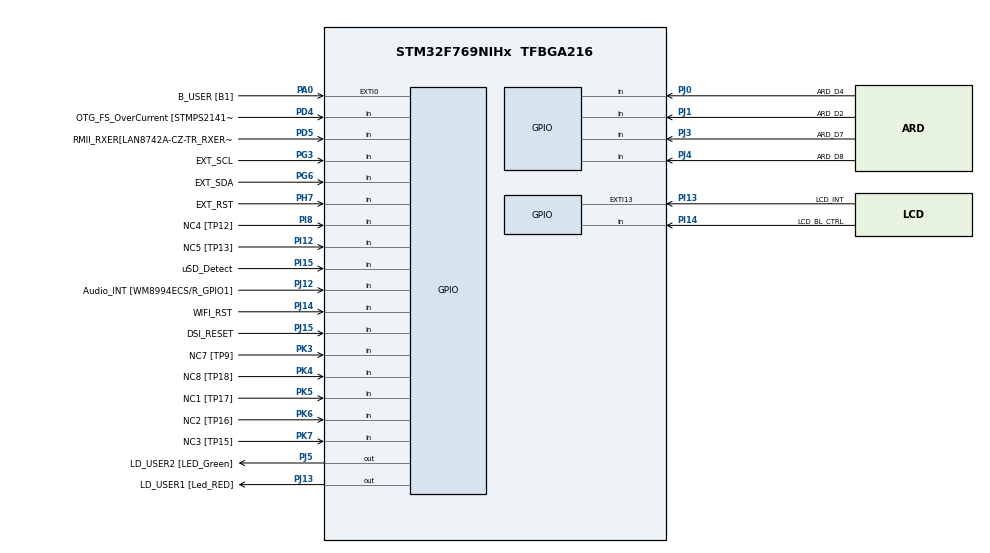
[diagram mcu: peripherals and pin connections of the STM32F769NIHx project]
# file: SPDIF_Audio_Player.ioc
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DSIHOST_CKN.GPIO_Label=DSI_CK_N
DSIHOST_CKN.Signal=DSIHOST_CKN
DSIHOST_CKP.GPIO_Label=DSI_CK_P
DSIHOST_CKP.Signal=DSIHOST_CKP
DSIHOST_D0N.GPIO_Label=DSI_D0_N
DSIHOST_D0N.Signal=DSIHOST_D0N
DSIHOST_D0P.GPIO_Label=DSI_D0_p
DSIHOST_D0P.Signal=DSIHOST_D0P
DSIHOST_D1N.GPIO_Label=DSI_D1_N
DSIHOST_D1N.Signal=DSIHOST_D1N
DSIHOST_D1P.GPIO_Label=DSI_D1_P
DSIHOST_D1P.Signal=DSIHOST_D1P
Mcu.Family=STM32F7
Mcu.Name=STM32F769NIHx
Mcu.Package=TFBGA216
NVIC.PriorityGroup=NVIC_PRIORITYGROUP_4
PA0/WKUP.GPIO_Label=B_USER [B1]
PA0/WKUP.Signal=GPXTI0
PA1.GPIO_Label=RMII_REF_CLK [LAN8742A-CZ-TR_REFCLK0]
PA1.Signal=ETH_REF_CLK
PA10.GPIO_Label=VCP_RX 
PA10.Signal=USART1_RX
PA11.GPIO_Label=SPI2_NSS
PA11.Signal=SPI2_NSS
PA12.GPIO_Label=ARD_D13/SCK
PA12.GPIO_Mode=GPIO_MODE_AF_PP
PA12.GPIO_PuPd=GPIO_NOPULL
PA12.GPIO_Speed=GPIO_SPEED_FREQ_LOW
PA12.Signal=SPI2_SCK
PA13.GPIO_Label=SWDIO
PA13.Signal=SYS_JTMS-SWDIO
PA14.GPIO_Label=SWCLK
PA14.Signal=SYS_JTCK-SWCLK
PA15.GPIO_Label=CEC
PA15.Signal=CEC
PA2.GPIO_Label=RMII_MDIO [LAN8742A-CZ-TR_MDIO]
PA2.Signal=ETH_MDIO
PA3.GPIO_Label=ULPI_D0 [USB3320C-EZK_D0]
PA3.Signal=USB_OTG_HS_ULPI_D0
PA4.GPIO_Label=ARD_A1
PA4.Signal=ADCx_IN4
PA5.GPIO_Label=ULPI_CLK [USB3320C-EZK_CLKOUT]
PA5.Signal=USB_OTG_HS_ULPI_CK
PA6.GPIO_Label=ARD_A0
PA6.Signal=ADCx_IN6
PA7.GPIO_Label=RMII_CRS_DV [LAN8742A-CZ-TR_CRS_DV]
PA7.Signal=ETH_CRS_DV
PA8.GPIO_Label=CEC_CLK [TP2]
PA8.Signal=RCC_MCO_1
PA9.GPIO_Label=VCP_TX [STM32F103CBT6_PA3]
PA9.GPIO_Mode=GPIO_MODE_AF_PP
PA9.GPIO_PuPd=GPIO_NOPULL
PA9.GPIO_Speed=GPIO_SPEED_FREQ_LOW
PA9.Signal=USART1_TX
PB0.GPIO_Label=ULPI_D1 [USB3320C-EZK_D1]
PB0.Signal=USB_OTG_HS_ULPI_D1
PB1.GPIO_Label=ULPI_D2 [USB3320C-EZK_D2]
PB1.Signal=USB_OTG_HS_ULPI_D2
PB10.GPIO_Label=ULPI_D3 [USB3320C-EZK_D3]
PB10.Signal=USB_OTG_HS_ULPI_D3
PB11.GPIO_Label=ULPI_D4 [USB3320C-EZK_D4]
PB11.Signal=USB_OTG_HS_ULPI_D4
PB12.GPIO_Label=ULPI_D5 [USB3320C-EZK_D5]
PB12.Signal=USB_OTG_HS_ULPI_D5
PB13.GPIO_Label=ULPI_D6 [USB3320C-EZK_D6]
PB13.Signal=USB_OTG_HS_ULPI_D6
PB14.GPIO_Label=ARDUINO MISO/D12
PB14.GPIO_Mode=GPIO_MODE_AF_PP
PB14.GPIO_PuPd=GPIO_NOPULL
PB14.GPIO_Speed=GPIO_SPEED_FREQ_LOW
PB14.Signal=SPI2_MISO
PB15.GPIO_Label=ARDUINO MOSI/PWM/D11
PB15.GPIO_Mode=GPIO_MODE_AF_PP
PB15.GPIO_PuPd=GPIO_NOPULL
PB15.GPIO_Speed=GPIO_SPEED_FREQ_LOW
PB15.Signal=SPI2_MOSI
PB2.Signal=QUADSPI_CLK
PB3.GPIO_Label=uSD_D2
PB3.Signal=SDMMC2_D2
PB4.GPIO_Label=uSD_D3
PB4.Signal=SDMMC2_D3
PB5.GPIO_Label=ULPI_D7 [USB3320C-EZK_D7]
PB5.Signal=USB_OTG_HS_ULPI_D7
PB6.GPIO_Label=QSPI_NCS [N25Q128A13EF840E_S]
PB6.Signal=QUADSPI_BK1_NCS
PB7.GPIO_Label=AUDIO_SDA [WM8994ECS/R_SDA]
PB7.Signal=I2C4_SDA
PB8.GPIO_Label=ARDUINO SCL/D15
PB8.GPIO_Mode=GPIO_MODE_AF_OD
PB8.GPIO_PuPd=GPIO_NOPULL
PB8.GPIO_Speed=GPIO_SPEED_FREQ_LOW
PB8.Signal=I2C1_SCL
PB9.GPIO_Label=ARDUINO SDA/D14
PB9.GPIO_Mode=GPIO_MODE_AF_OD
PB9.GPIO_PuPd=GPIO_NOPULL
PB9.GPIO_Speed=GPIO_SPEED_FREQ_LOW
PB9.Signal=I2C1_SDA
PC0.GPIO_Label=ULPI_STP [USB3320C-EZK_STP]
PC0.Signal=USB_OTG_HS_ULPI_STP
PC1.GPIO_Label=RMII_MDC [LAN8742A-CZ-TR_MDC]
PC1.Signal=ETH_MDC
PC10.GPIO_Label=QSPI_D1 [MT25QL512ABB1EW9_DQ1]
PC10.Signal=QUADSPI_BK1_IO1
PC11.GPIO_Label=DFSDM_DATIN5 [TP100]
PC11.Signal=S_DATAIN5DFSDM1
PC12.GPIO_Label=WIFI_RX
PC12.Signal=UART5_TX
PC14/OSC32_IN.GPIO_Label=RCC_OSC32_IN
PC14/OSC32_IN.Signal=RCC_OSC32_IN
PC15/OSC32_OUT.GPIO_Label=RCC_OSC32_OUT
PC15/OSC32_OUT.Signal=RCC_OSC32_OUT
PC2.GPIO_Label=ARD_A2
PC2.Signal=ADCx_IN12
PC3.GPIO_Label=DFSDM_DATIN1 [TP101]
PC3.Signal=S_DATAIN1DFSDM1
PC4.GPIO_Label=RMII_RXD0 [LAN8742A-CZ-TR_RXD0]
PC4.Signal=ETH_RXD0
PC5.GPIO_Label=RMII_RXD1 [LAN8742A-CZ-TR_RXD1]
PC5.Signal=ETH_RXD1
PC6.GPIO_Label=ARDUINO TX/D1
PC6.Signal=USART6_TX
PC7.GPIO_Label=ARD_D0/RX
PC7.Signal=USART6_RX
PC8.GPIO_Label=ARD_D5/PWM
PC8.Signal=S_TIM3_CH3
PC9.GPIO_Label=QSPI_D0 [N25Q128A13EF840E_DQ0]
PC9.Signal=QUADSPI_BK1_IO0
PD0.GPIO_Label=FMC_D2 [MT48LC4M32B2B5-6A_DQ2]
PD0.Signal=FMC_D2_DA2
PD1.GPIO_Label=FMC_D3 [MT48LC4M32B2B5-6A_DQ3]
PD1.Signal=FMC_D3_DA3
PD10.GPIO_Label=FMC_D15 [MT48LC4M32B2B5-6A_DQ15]
PD10.Signal=FMC_D15_DA15
PD11.GPIO_Label=SPDIF_TX [TP20]
PD11.Signal=SAI2_SD_A
PD12.GPIO_Label=AUDIO_SCL [WM8994ECS/R_SCLK]
PD12.Signal=I2C4_SCL
PD13.GPIO_Label=QSPI_D3 [N25Q128A13EF840E_DQ3]
PD13.Signal=QUADSPI_BK1_IO3
PD14.GPIO_Label=FMC_D0 [MT48LC4M32B2B5-6A_DQ0]
PD14.Signal=FMC_D0_DA0
PD15.GPIO_Label=FMC_D1 [MT48LC4M32B2B5-6A_DQ1]
PD15.Signal=FMC_D1_DA1
PD2.GPIO_Label=WIFI_TX
PD2.Signal=UART5_RX
PD3.GPIO_Label=DFSDM_CKOUT [TP102]
PD3.Signal=S_CKOUTDFSDM1
PD4.GPIO_Label=OTG_FS_OverCurrent [STMPS2141STR_Fault]
PD4.Signal=GPIO_Input
PD5.GPIO_Label=RMII_RXER[LAN8742A-CZ-TR_RXERR]
PD5.Signal=GPIO_Input
PD6.GPIO_Label=uSD_CLK
PD6.Signal=SDMMC2_CK
PD7.GPIO_Label=uSD_CMD
PD7.Signal=SDMMC2_CMD
PD8.GPIO_Label=FMC_D13 [MT48LC4M32B2B5-6A_DQ13]
PD8.Signal=FMC_D13_DA13
PD9.GPIO_Label=FMC_D14 [MT48LC4M32B2B5-6A_DQ14]
PD9.Signal=FMC_D14_DA14
PE0.GPIO_Label=FMC_NBL0 [MT48LC4M32B2B5-6A_DQM0]
PE0.Signal=FMC_NBL0
PE1.GPIO_Label=FMC_NBL1 [MT48LC4M32B2B5-6A_DQM1]
PE1.Signal=FMC_NBL1
PE10.GPIO_Label=FMC_D7 [MT48LC4M32B2B5-6A_DQ7]
PE10.Signal=FMC_D7_DA7
PE11.GPIO_Label=FMC_D8 [MT48LC4M32B2B5-6A_DQ8]
PE11.Signal=FMC_D8_DA8
PE12.GPIO_Label=FMC_D9 [MT48LC4M32B2B5-6A_DQ9]
PE12.Signal=FMC_D9_DA9
PE13.GPIO_Label=FMC_D10 [MT48LC4M32B2B5-6A_DQ10]
PE13.Signal=FMC_D10_DA10
PE14.GPIO_Label=FMC_D11 [MT48LC4M32B2B5-6A_DQ11]
PE14.Signal=FMC_D11_DA11
PE15.GPIO_Label=FMC_D12 [MT48LC4M32B2B5-6A_DQ12]
PE15.Signal=FMC_D12_DA12
PE2.GPIO_Label=QSPI_D2 [N25Q128A13EF840E_DQ2]
PE2.Signal=QUADSPI_BK1_IO2
PE3.GPIO_Label=SAI1_SDB [WM8994ECS/R_ADCDAT1]
PE3.Signal=SAI1_SD_B
PE4.GPIO_Label=SAI1_FSA [WM8994ECS/R_LRCLK1]
PE4.Signal=SAI1_FS_A
PE5.GPIO_Label=SAI1_SCKA [WM8994ECS/R_BCLK1]
PE5.Signal=SAI1_SCK_A
PE6.GPIO_Label=SAI1_SDA [WM8994ECS/R_DACDAT1]
PE6.Signal=SAI1_SD_A
PE7.GPIO_Label=FMC_D4 [MT48LC4M32B2B5-6A_DQ4]
PE7.Signal=FMC_D4_DA4
PE8.GPIO_Label=FMC_D5 [MT48LC4M32B2B5-6A_DQ5]
PE8.Signal=FMC_D5_DA5
PE9.GPIO_Label=FMC_D6 [MT48LC4M32B2B5-6A_DQ6]
PE9.Signal=FMC_D6_DA6
PF0.GPIO_Label=FMC_A0 [MT48LC4M32B2B5-6A_A0]
PF0.Signal=FMC_A0
PF1.GPIO_Label=FMC_A1 [MT48LC4M32B2B5-6A_A1]
PF1.Signal=FMC_A1
PF10.GPIO_Label=ARDUINO A1
PF10.GPIO_Mode=GPIO_MODE_ANALOG
PF10.GPIO_PuPd=GPIO_NOPULL
PF10.Signal=ADC3_IN8
PF11.GPIO_Label=FMC_SDNRAS [MT48LC4M32B2B5-6A_RAS]
PF11.Signal=FMC_SDNRAS
PF12.GPIO_Label=FMC_A6 [MT48LC4M32B2B5-6A_A6]
PF12.Signal=FMC_A6
PF13.GPIO_Label=FMC_A7 [MT48LC4M32B2B5-6A_A7]
PF13.Signal=FMC_A7
PF14.GPIO_Label=FMC_A8 [MT48LC4M32B2B5-6A_A8]
PF14.Signal=FMC_A8
PF15.GPIO_Label=FMC_A9 [MT48LC4M32B2B5-6A_A9]
PF15.Signal=FMC_A9
PF2.GPIO_Label=FMC_A2 [MT48LC4M32B2B5-6A_A2]
PF2.Signal=FMC_A2
PF3.GPIO_Label=FMC_A3 [MT48LC4M32B2B5-6A_A3]
PF3.Signal=FMC_A3
PF4.GPIO_Label=FMC_A4 [MT48LC4M32B2B5-6A_A4]
PF4.Signal=FMC_A4
PF5.GPIO_Label=FMC_A5 [MT48LC4M32B2B5-6A_A5]
PF5.Signal=FMC_A5
PF6.GPIO_Label=ARD_D3/PWM
PF6.Signal=S_TIM10_CH1
PF7.GPIO_Label=ARD_D6/PWM
PF7.Signal=S_TIM11_CH1
PF8.GPIO_Label=ARDUINO A3
PF8.GPIO_Mode=GPIO_MODE_ANALOG
PF8.GPIO_PuPd=GPIO_NOPULL
PF8.Signal=ADC3_IN6
PF9.GPIO_Label=ARDUINO A2
PF9.GPIO_Mode=GPIO_MODE_ANALOG
PF9.GPIO_PuPd=GPIO_NOPULL
PF9.Signal=ADC3_IN7
PG0.GPIO_Label=FMC_A10 [MT48LC4M32B2B5-6A_A10]
PG0.Signal=FMC_A10
PG1.GPIO_Label=FMC_A11 [MT48LC4M32B2B5-6A_A11]
PG1.Signal=FMC_A11
PG10.GPIO_Label=uSD_D1
PG10.Signal=SDMMC2_D1
PG11.GPIO_Label=RMII_TX_EN [LAN8742A-CZ-TR_TXEN]
PG11.Signal=ETH_TX_EN
PG12.GPIO_Label=SPDIF_RX [74LVC1G04SE_4]
PG12.Signal=SPDIFRX_IN1
PG13.GPIO_Label=RMII_TXD0 [LAN8742A-CZ-TR_TXD0]
PG13.Signal=ETH_TXD0
PG14.GPIO_Label=RMII_TXD1 [LAN8742A-CZ-TR_TXD1]
PG14.Signal=ETH_TXD1
PG15.GPIO_Label=FMC_SDNCAS [MT48LC4M32B2B5-6A_CAS]
PG15.Signal=FMC_SDNCAS
PG2.GPIO_Label=FMC_A12
PG2.Signal=FMC_A12
PG3.GPIO_Label=EXT_SCL
PG3.Signal=GPIO_Input
PG4.GPIO_Label=FMC_BA0 [MT48LC4M32B2B5-6A_BA0]
PG4.Signal=FMC_A14_BA0
PG5.GPIO_Label=FMC_BA1 [MT48LC4M32B2B5-6A_BA1]
PG5.Signal=FMC_A15_BA1
PG6.GPIO_Label=EXT_SDA
PG6.Signal=GPIO_Input
PG7.GPIO_Label=SAI1_MCLKA [WM8994ECS/R_MCLK1]
PG7.Signal=SAI1_MCLK_A
PG8.GPIO_Label=FMC_SDCLK [MT48LC4M32B2B5-6A_CLK]
PG8.Signal=FMC_SDCLK
PG9.GPIO_Label=uSD_D0
PG9.Signal=SDMMC2_D0
PH0/OSC_IN.GPIO_Label=OSC_25M [NZ2520SB-25.00M_OUT]
PH0/OSC_IN.Signal=RCC_OSC_IN
PH1/OSC_OUT.Signal=RCC_OSC_OUT
PH10.GPIO_Label=FMC_D18 [MT48LC4M32B2B5-6A_DQ18]
PH10.Signal=FMC_D18
PH11.GPIO_Label=FMC_D19 [MT48LC4M32B2B5-6A_DQ19]
PH11.Signal=FMC_D19
PH12.GPIO_Label=D20
PH12.Signal=FMC_D20
PH13.GPIO_Label=D21
PH13.Signal=FMC_D21
PH14.GPIO_Label=D22
PH14.Signal=FMC_D22
PH15.GPIO_Label=D23
PH15.Signal=FMC_D23
PH2.GPIO_Label=FMC_SDCKE0 [MT48LC4M32B2B5-6A_CKE]
PH2.Signal=FMC_SDCKE0
PH3.GPIO_Label=FMC_SDNE0 [MT48LC4M32B2B5-6A_CS]
PH3.Signal=FMC_SDNE0
PH4.GPIO_Label=ULPI_NXT [USB3320C-EZK_NXT]
PH4.Signal=USB_OTG_HS_ULPI_NXT
PH5.GPIO_Label=FMC_SDNME [MT48LC4M32B2B5-6A_WE]
PH5.Signal=FMC_SDNWE
PH6.GPIO_Label=ARDUINO PWM/D6
PH6.Signal=S_TIM12_CH1
PH7.GPIO_Label=EXT_RST
PH7.Signal=GPIO_Input
PH8.GPIO_Label=FMC_D16 [MT48LC4M32B2B5-6A_DQ16]
PH8.Signal=FMC_D16
PH9.GPIO_Label=FMC_D\!7 [MT48LC4M32B2B5-6A_DQ17]
PH9.Signal=FMC_D17
PI0.GPIO_Label=D24
PI0.Signal=FMC_D24
PI1.GPIO_Label=D25
PI1.Signal=FMC_D25
PI10.GPIO_Label=D31
PI10.Signal=FMC_D31
PI11.GPIO_Label=ULPI_DIR [USB3320C-EZK_DIR]
PI11.Signal=USB_OTG_HS_ULPI_DIR
PI12.GPIO_Label=NC5 [TP13]
PI12.Signal=GPIO_Input
PI13.GPIO_Label=LCD_INT
PI13.GPIO_ModeDefaultEXTI=GPIO_MODE_EVT_RISING
PI13.Signal=GPXTI13
PI14.GPIO_Label=LCD_BL_CTRL
PI14.Signal=GPIO_Input
PI15.GPIO_Label=uSD_Detect
PI15.Signal=GPIO_Input
PI2.GPIO_Label=D26
PI2.Signal=FMC_D26
PI3.GPIO_Label=D27
PI3.Signal=FMC_D27
PI4.GPIO_Label=FMC_NBL2 [MT48LC4M32B2B5-6A_DQM2]
PI4.Signal=FMC_NBL2
PI5.GPIO_Label=FMC_NBL3 [MT48LC4M32B2B5-6A_DQM3]
PI5.Signal=FMC_NBL3
PI6.GPIO_Label=D28
PI6.Signal=FMC_D28
PI7.GPIO_Label=D29
PI7.Signal=FMC_D29
PI8.GPIO_Label=NC4 [TP12]
PI8.Signal=GPIO_Input
PI9.GPIO_Label=D30
PI9.Signal=FMC_D30
PJ0.GPIO_Label=ARD_D4
PJ0.Signal=GPIO_Input
PJ1.GPIO_Label=ARD_D2
PJ1.Signal=GPIO_Input
PJ12.GPIO_Label=Audio_INT [WM8994ECS/R_GPIO1]
PJ12.Signal=GPIO_Input
PJ13.GPIO_Label=LD_USER1 [Led_RED]
PJ13.Signal=GPIO_Output
PJ14.GPIO_Label=WIFI_RST
PJ14.Signal=GPIO_Input
PJ15.GPIO_Label=DSI_RESET
PJ15.Signal=GPIO_Input
PJ2.GPIO_Label=DSIHOST_TE
PJ2.Signal=DSIHOST_TE
PJ3.GPIO_Label=ARD_D7
PJ3.Signal=GPIO_Input
PJ4.GPIO_Label=ARD_D8
PJ4.Signal=GPIO_Input
PJ5.GPIO_Label=LD_USER2 [LED_Green]
PJ5.Signal=GPIO_Output
PK3.GPIO_Label=NC7 [TP9]
PK3.Signal=GPIO_Input
PK4.GPIO_Label=NC8 [TP18]
PK4.Signal=GPIO_Input
PK5.GPIO_Label=NC1 [TP17]
PK5.Signal=GPIO_Input
PK6.GPIO_Label=NC2 [TP16]
PK6.Signal=GPIO_Input
PK7.GPIO_Label=NC3 [TP15]
PK7.Signal=GPIO_Input
ProjectManager.HeapSize=0x200
ProjectManager.StackSize=0x400
ProjectManager.TargetToolchain=STM32CubeIDE
RCC.AHBFreq_Value=96000000
RCC.APB1CLKDivider=RCC_HCLK_DIV4
RCC.APB1Freq_Value=24000000
RCC.APB1TimFreq_Value=48000000
RCC.APB2CLKDivider=RCC_HCLK_DIV2
RCC.APB2Freq_Value=48000000
RCC.APB2TimFreq_Value=96000000
RCC.CortexFreq_Value=96000000
RCC.HCLKFreq_Value=96000000
RCC.HSE_VALUE=25000000
RCC.HSI_VALUE=16000000
RCC.LSE_VALUE=32768
RCC.PLLM=8
RCC.PLLP=RCC_PLLP_DIV4
RCC.PLLQ=4
RCC.PLLSAIQ=3
RCC.SYSCLKFreq_VALUE=96000000
RCC.SYSCLKSource=RCC_SYSCLKSOURCE_PLLCLK
RCC.USBFreq_Value=96000000
RCC.VCOOutputFreq_Value=384000000
SH.ADCx_IN12.0=ADC1_IN12
SH.ADCx_IN4.0=ADC1_IN4
SH.ADCx_IN6.0=ADC1_IN6
SH.FMC_A0.0=FMC_A0
SH.FMC_A1.0=FMC_A1
SH.FMC_A10.0=FMC_A10
SH.FMC_A11.0=FMC_A11
SH.FMC_A12.0=FMC_A12
SH.FMC_A14_BA0.0=FMC_BA0
SH.FMC_A15_BA1.0=FMC_BA1
SH.FMC_A2.0=FMC_A2
SH.FMC_A3.0=FMC_A3
SH.FMC_A4.0=FMC_A4
SH.FMC_A5.0=FMC_A5
SH.FMC_A6.0=FMC_A6
SH.FMC_A7.0=FMC_A7
SH.FMC_A8.0=FMC_A8
SH.FMC_A9.0=FMC_A9
SH.FMC_D0_DA0.0=FMC_D0
SH.FMC_D10_DA10.0=FMC_D10
SH.FMC_D11_DA11.0=FMC_D11
SH.FMC_D12_DA12.0=FMC_D12
SH.FMC_D13_DA13.0=FMC_D13
SH.FMC_D14_DA14.0=FMC_D14
SH.FMC_D15_DA15.0=FMC_D15
SH.FMC_D16.0=FMC_D16
SH.FMC_D17.0=FMC_D17
SH.FMC_D18.0=FMC_D18
SH.FMC_D19.0=FMC_D19
SH.FMC_D1_DA1.0=FMC_D1
SH.FMC_D20.0=FMC_D20
SH.FMC_D21.0=FMC_D21
SH.FMC_D22.0=FMC_D22
SH.FMC_D23.0=FMC_D23
SH.FMC_D24.0=FMC_D24
SH.FMC_D25.0=FMC_D25
SH.FMC_D26.0=FMC_D26
SH.FMC_D27.0=FMC_D27
SH.FMC_D28.0=FMC_D28
SH.FMC_D29.0=FMC_D29
SH.FMC_D2_DA2.0=FMC_D2
SH.FMC_D30.0=FMC_D30
SH.FMC_D31.0=FMC_D31
SH.FMC_D3_DA3.0=FMC_D3
SH.FMC_D4_DA4.0=FMC_D4
SH.FMC_D5_DA5.0=FMC_D5
SH.FMC_D6_DA6.0=FMC_D6
SH.FMC_D7_DA7.0=FMC_D7
SH.FMC_D8_DA8.0=FMC_D8
SH.FMC_D9_DA9.0=FMC_D9
SH.FMC_NBL0.0=FMC_NBL0
SH.FMC_NBL1.0=FMC_NBL1
SH.FMC_NBL2.0=FMC_NBL2
SH.FMC_NBL3.0=FMC_NBL3
SH.FMC_SDCLK.0=FMC_SDCLK
SH.FMC_SDNCAS.0=FMC_SDNCAS
SH.FMC_SDNRAS.0=FMC_SDNRAS
SH.FMC_SDNWE.0=FMC_SDNWE
SH.S_CKOUTDFSDM1.0=DFSDM1_CKOUT
SH.S_DATAIN1DFSDM1.0=DFSDM1_DATIN1
SH.S_DATAIN5DFSDM1.0=DFSDM1_DATIN5
SH.S_TIM10_CH1.0=TIM10_CH1
SH.S_TIM11_CH1.0=TIM11_CH1
SH.S_TIM12_CH1.0=TIM12_CH1
SH.S_TIM3_CH3.0=TIM3_CH3
board=STM32F769I-DISCO

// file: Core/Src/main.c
/* USER CODE BEGIN Header */
/**
  ******************************************************************************
  * @file           : main.c
  * @brief          : Main program body
  ******************************************************************************
  * @attention
  *
  * Copyright (c) 2022 STMicroelectronics.
  * All rights reserved.
  *
  * This software is licensed under terms that can be found in the LICENSE file
  * in the root directory of this software component.
  * If no LICENSE file comes with this software, it is provided AS-IS.
  *
  ******************************************************************************
  */
/* USER CODE END Header */
#include "tasks.h"
#include "stlogo.h"
/* USER CODE END Includes */

/* USER CODE BEGIN PV */
__IO uint8_t DemoIndex = 0;
__IO uint8_t NbLoop = 1;
__IO uint32_t SdmmcTest = 0;
__IO uint32_t SdramTest = 0;

SemaphoreHandle_t xSemaphoreAudioOUT = NULL;
SemaphoreHandle_t xSemaphoreLCD = NULL;

/* USER CODE END PV */

void SystemClock_Config(void);
static void MPU_Config(void);
void SystemClock_Config(void);
static void CPU_CACHE_Enable(void);

osThreadId_t defaultTaskHandle; //Used for displaying VU Meter or something else to LCD
osThreadId_t starterTaskHandle; //Used to setup SPDIF, wait for signal disconnect
osThreadId_t playerTaskHandle;  //Used to feeding audio to SAI

const osThreadAttr_t defaultTask_attributes = {
		  .name = "defaultTask",
		  .stack_size = 512 * 4,
		  .priority = (osPriority_t) osPriorityNormal,		// osPriorityLow,
		};
const osThreadAttr_t starterTask_attributes = {
		  .name = "starterTask",
		  .stack_size = 512 * 4,
		  .priority = (osPriority_t) osPriorityNormal,		//osPriorityHigh,
		};
const osThreadAttr_t playerTask_attributes = {
		  .name = "playerTask",
		  .stack_size = 512 * 4,
		  .priority = (osPriority_t) osPriorityNormal,
		};

int main(void)
{
  /* USER CODE BEGIN 1 */

  /* Configure the MPU attributes */
  MPU_Config();

  /* Enable the CPU Cache */
  CPU_CACHE_Enable();
  /* USER CODE END 1 */

  /* MCU Configuration--------------------------------------------------------*/

  /* Reset of all peripherals, Initializes the Flash interface and the Systick. */
  HAL_Init();

  /* Configure the system clock */
  SystemClock_Config();

  /* USER CODE BEGIN 2 */
  BSP_LED_Init(LED_GREEN);
  BSP_LED_Init(LED_RED);

  /* Configure the Tamper push-button in GPIO Mode */
  BSP_PB_Init(BUTTON_WAKEUP, BUTTON_MODE_GPIO);

#if IT_FAILS_THIS_WAY
  BSP_AUDIO_OUT_Init(OUTPUT_DEVICE_HEADPHONE /*OUTPUT_DEVICE_AUTO*/, 90, 48000);
#endif

#if 1
  {
	  /* Initialize the LCD */
	  uint8_t  lcd_status = LCD_OK;
	  lcd_status = BSP_LCD_Init();
	  while(lcd_status != LCD_OK);

	  BSP_LCD_LayerDefaultInit(0, LCD_FB_START_ADDRESS);
	  BSP_LCD_Clear(LCD_COLOR_WHITE);
	  /* Set LCD Foreground Layer  */
	  BSP_LCD_SelectLayer(0);
	  BSP_LCD_SetFont(&LCD_DEFAULT_FONT);
	  /* Clear the LCD */
	  BSP_LCD_SetBackColor(LCD_COLOR_WHITE);
	  BSP_LCD_Clear(LCD_COLOR_WHITE);
  }
#endif

  /* USER CODE END 2 */

  /* Init scheduler */
  osKernelInitialize();

  /* Create the thread(s) */
  /* creation of defaultTask */

  vSemaphoreCreateBinary(xSemaphoreAudioOUT);
  xSemaphoreTake(xSemaphoreAudioOUT, 0);
  vSemaphoreCreateBinary(xSemaphoreLCD);
  xSemaphoreTake(xSemaphoreLCD, 0);

  defaultTaskHandle = osThreadNew(StartDefaultTask, NULL, &defaultTask_attributes); //Used for displaying VU Meter or something else to LCD
  playerTaskHandle = osThreadNew(playerTask, NULL, &playerTask_attributes); //Used to feeding audio to SAI
  starterTaskHandle = osThreadNew(starterTask, NULL, &starterTask_attributes); //Used to setup SPDIF, wait for signal disconnect

  /* Start scheduler */
  osKernelStart();

  /* We should never get here as control is now taken by the scheduler */
  /* Infinite loop */
  while (1)
  {

  }
}

void SystemClock_Config(void)
{
  RCC_ClkInitTypeDef RCC_ClkInitStruct;
  RCC_OscInitTypeDef RCC_OscInitStruct;
  HAL_StatusTypeDef ret = HAL_OK;

  /* Enable HSE Oscillator and activate PLL with HSE as source */
  RCC_OscInitStruct.OscillatorType = RCC_OSCILLATORTYPE_HSE;
  RCC_OscInitStruct.HSEState = RCC_HSE_ON;
  RCC_OscInitStruct.PLL.PLLState = RCC_PLL_ON;
  RCC_OscInitStruct.PLL.PLLSource = RCC_PLLSOURCE_HSE;
  RCC_OscInitStruct.PLL.PLLM = 25;
  RCC_OscInitStruct.PLL.PLLN = 400;
  RCC_OscInitStruct.PLL.PLLP = RCC_PLLP_DIV2;
  RCC_OscInitStruct.PLL.PLLQ = 8;
  RCC_OscInitStruct.PLL.PLLR = 7;

  ret = HAL_RCC_OscConfig(&RCC_OscInitStruct);
  if(ret != HAL_OK)
  {
    while(1) { ; }
  }

  /* Activate the OverDrive to reach the 200 MHz Frequency */
  ret = HAL_PWREx_EnableOverDrive();
  if(ret != HAL_OK)
  {
    while(1) { ; }
  }

  /* Select PLL as system clock source and configure the HCLK, PCLK1 and PCLK2 clocks dividers */
  RCC_ClkInitStruct.ClockType = (RCC_CLOCKTYPE_SYSCLK | RCC_CLOCKTYPE_HCLK | RCC_CLOCKTYPE_PCLK1 | RCC_CLOCKTYPE_PCLK2);
  RCC_ClkInitStruct.SYSCLKSource = RCC_SYSCLKSOURCE_PLLCLK;
  RCC_ClkInitStruct.AHBCLKDivider = RCC_SYSCLK_DIV1;
  RCC_ClkInitStruct.APB1CLKDivider = RCC_HCLK_DIV4;
  RCC_ClkInitStruct.APB2CLKDivider = RCC_HCLK_DIV2;

  ret = HAL_RCC_ClockConfig(&RCC_ClkInitStruct, FLASH_LATENCY_6);
  if(ret != HAL_OK)
  {
    while(1) { ; }
  }
}

/* USER CODE BEGIN 4 */

/**
  * @brief  Configure the MPU attributes
  * @param  None
  * @retval None
  */
static void MPU_Config(void)
{
  MPU_Region_InitTypeDef MPU_InitStruct;

  /* Disable the MPU */
  HAL_MPU_Disable();

  /* Configure the MPU as Strongly ordered for not defined regions */
  MPU_InitStruct.Enable = MPU_REGION_ENABLE;
  MPU_InitStruct.BaseAddress = 0x00;
  MPU_InitStruct.Size = MPU_REGION_SIZE_4GB;
  MPU_InitStruct.AccessPermission = MPU_REGION_NO_ACCESS;
  MPU_InitStruct.IsBufferable = MPU_ACCESS_NOT_BUFFERABLE;
  MPU_InitStruct.IsCacheable = MPU_ACCESS_NOT_CACHEABLE;
  MPU_InitStruct.IsShareable = MPU_ACCESS_SHAREABLE;
  MPU_InitStruct.Number = MPU_REGION_NUMBER0;
  MPU_InitStruct.TypeExtField = MPU_TEX_LEVEL0;
  MPU_InitStruct.SubRegionDisable = 0x87;
  MPU_InitStruct.DisableExec = MPU_INSTRUCTION_ACCESS_DISABLE;

  HAL_MPU_ConfigRegion(&MPU_InitStruct);

  /* Configure the MPU attributes as WT for SDRAM */
  MPU_InitStruct.Enable = MPU_REGION_ENABLE;
  MPU_InitStruct.BaseAddress = 0xC0000000;
  MPU_InitStruct.Size = MPU_REGION_SIZE_32MB;
  MPU_InitStruct.AccessPermission = MPU_REGION_FULL_ACCESS;
  MPU_InitStruct.IsBufferable = MPU_ACCESS_NOT_BUFFERABLE;
  MPU_InitStruct.IsCacheable = MPU_ACCESS_CACHEABLE;
  MPU_InitStruct.IsShareable = MPU_ACCESS_NOT_SHAREABLE;
  MPU_InitStruct.Number = MPU_REGION_NUMBER1;
  MPU_InitStruct.TypeExtField = MPU_TEX_LEVEL0;
  MPU_InitStruct.SubRegionDisable = 0x00;
  MPU_InitStruct.DisableExec = MPU_INSTRUCTION_ACCESS_ENABLE;

  HAL_MPU_ConfigRegion(&MPU_InitStruct);

  /* Configure the MPU QSPI flash */
  MPU_InitStruct.Enable = MPU_REGION_ENABLE;
  MPU_InitStruct.BaseAddress = 0x90000000;
  MPU_InitStruct.Size = MPU_REGION_SIZE_64MB;
  MPU_InitStruct.AccessPermission = MPU_REGION_FULL_ACCESS;
  MPU_InitStruct.IsBufferable = MPU_ACCESS_NOT_BUFFERABLE;
  MPU_InitStruct.IsCacheable = MPU_ACCESS_CACHEABLE;
  MPU_InitStruct.IsShareable = MPU_ACCESS_NOT_SHAREABLE;
  MPU_InitStruct.Number = MPU_REGION_NUMBER2;
  MPU_InitStruct.TypeExtField = MPU_TEX_LEVEL0;
  MPU_InitStruct.SubRegionDisable = 0x0;
  MPU_InitStruct.DisableExec = MPU_INSTRUCTION_ACCESS_ENABLE;

  HAL_MPU_ConfigRegion(&MPU_InitStruct);

  /* Configure the MPU attributes FMC control registers */
  MPU_InitStruct.Enable = MPU_REGION_ENABLE;
  MPU_InitStruct.BaseAddress = 0xA0000000;
  MPU_InitStruct.Size = MPU_REGION_SIZE_8KB;
  MPU_InitStruct.AccessPermission = MPU_REGION_FULL_ACCESS;
  MPU_InitStruct.IsBufferable = MPU_ACCESS_BUFFERABLE;
  MPU_InitStruct.IsCacheable = MPU_ACCESS_NOT_CACHEABLE;
  MPU_InitStruct.IsShareable = MPU_ACCESS_SHAREABLE;
  MPU_InitStruct.Number = MPU_REGION_NUMBER3;
  MPU_InitStruct.TypeExtField = MPU_TEX_LEVEL0;
  MPU_InitStruct.SubRegionDisable = 0x0;
  MPU_InitStruct.DisableExec = MPU_INSTRUCTION_ACCESS_DISABLE;

  HAL_MPU_ConfigRegion(&MPU_InitStruct);

  /* Enable the MPU */
  HAL_MPU_Enable(MPU_PRIVILEGED_DEFAULT);
}

#ifdef  USE_FULL_ASSERT

/**
  * @brief  Reports the name of the source file and the source line number
  *         where the assert_param error has occurred.
  * @param  file: pointer to the source file name
  * @param  line: assert_param error line source number
  * @retval None
  */
void assert_failed(uint8_t* file, uint32_t line)
{
  /* User can add his own implementation to report the file name and line number,
     ex: printf("Wrong parameters value: file %s on line %d\r\n", file, line) */

  /* Infinite loop */
  while (1)
  {
  }
}
#endif /* USE_FULL_ASSERT */

/**
  * @brief  CPU L1-Cache enable.
  * @param  None
  * @retval None
  */
static void CPU_CACHE_Enable(void)
{
  /* Enable I-Cache */
  SCB_EnableICache();

  /* Enable D-Cache */
  SCB_EnableDCache();
}

/**
  * @brief  Check for user input
  * @param  None
* @retval Input state (1 : active / 0 : Inactive)
  */
uint8_t CheckForUserInput(void)
{
  if(BSP_PB_GetState(BUTTON_WAKEUP) == GPIO_PIN_SET)
  {
    while (BSP_PB_GetState(BUTTON_WAKEUP) == GPIO_PIN_SET);
    return 1 ;
  }
  return 0;
}

/**
  * @brief  EXTI line detection callbacks.
  * @param  GPIO_Pin: Specifies the pins connected EXTI line
  * @retval None
  */
void HAL_GPIO_EXTI_Callback(uint16_t GPIO_Pin)
{
	BSP_LED_Toggle(LED_GREEN);
}

/* USER CODE END 4 */

void Error_Handler(void)
{
  /* USER CODE BEGIN Error_Handler_Debug */
  /* User can add his own implementation to report the HAL error return state */
  __disable_irq();
  BSP_LED_On(LED_RED);
  while (1)
  {
  }
  /* USER CODE END Error_Handler_Debug */
}
